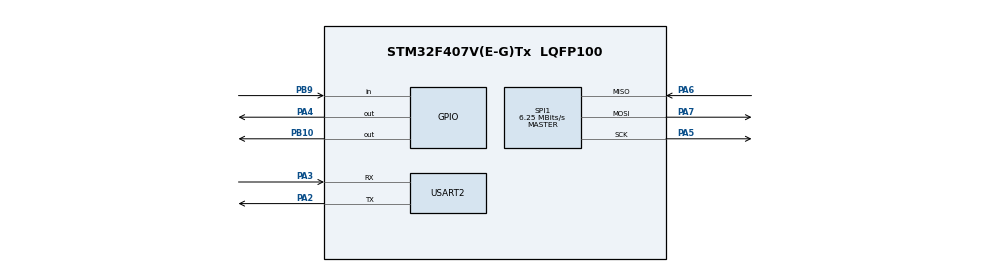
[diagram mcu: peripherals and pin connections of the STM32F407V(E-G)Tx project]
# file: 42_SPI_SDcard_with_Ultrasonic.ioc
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Mcu.Family=STM32F4
Mcu.Name=STM32F407V(E-G)Tx
Mcu.Package=LQFP100
NVIC.PriorityGroup=NVIC_PRIORITYGROUP_0
PA2.Mode=Asynchronous
PA2.Signal=USART2_TX
PA3.Mode=Asynchronous
PA3.Signal=USART2_RX
PA4.Signal=GPIO_Output
PA5.Mode=Full_Duplex_Master
PA5.Signal=SPI1_SCK
PA6.Mode=Full_Duplex_Master
PA6.Signal=SPI1_MISO
PA7.Mode=Full_Duplex_Master
PA7.Signal=SPI1_MOSI
PB10.Signal=GPIO_Output
PB9.Signal=GPIO_Input
PH0-OSC_IN.Mode=HSE-External-Oscillator
PH0-OSC_IN.Signal=RCC_OSC_IN
PH1-OSC_OUT.Mode=HSE-External-Oscillator
PH1-OSC_OUT.Signal=RCC_OSC_OUT
ProjectManager.HeapSize=0x200
ProjectManager.StackSize=0x400
ProjectManager.TargetToolchain=STM32CubeIDE
RCC.48MHZClocksFreq_Value=14285714.285714285
RCC.AHBFreq_Value=25000000
RCC.APB1CLKDivider=RCC_HCLK_DIV4
RCC.APB1Freq_Value=6250000
RCC.APB1TimFreq_Value=12500000
RCC.APB2CLKDivider=RCC_HCLK_DIV2
RCC.APB2Freq_Value=12500000
RCC.APB2TimFreq_Value=25000000
RCC.CortexFreq_Value=25000000
RCC.HCLKFreq_Value=25000000
RCC.HSE_VALUE=8000000
RCC.HSI_VALUE=16000000
RCC.LSE_VALUE=32768
RCC.PLLM=8
RCC.PLLN=50
RCC.PLLP=RCC_PLLP_DIV4
RCC.PLLQ=7
RCC.SYSCLKFreq_VALUE=25000000
RCC.SYSCLKSource=RCC_SYSCLKSOURCE_PLLCLK
RCC.VCOOutputFreq_Value=100000000
SPI1.CalculateBaudRate=6.25 MBits/s
SPI1.Direction=SPI_DIRECTION_2LINES
SPI1.Mode=SPI_MODE_MASTER
SPI1.VirtualType=VM_MASTER
USART2.VirtualMode=VM_ASYNC
VP_FATFS_VS_Generic.Mode=User_defined
VP_TIM3_VS_ClockSourceINT.Mode=Internal
board=STM32F407G-DISC1

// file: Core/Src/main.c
/* USER CODE BEGIN Header */
/* USER CODE END Header */
#include "main.h"
#include "fatfs.h"
#include "stdio.h"
#include "string.h"

/* USER CODE BEGIN PD */
#define TRIG_PORT GPIOB
#define TRIG_PIN  GPIO_PIN_10

#define ECHO_PORT GPIOB
#define ECHO_PIN  GPIO_PIN_9
/* USER CODE END PD */

SPI_HandleTypeDef hspi1;

TIM_HandleTypeDef htim3;

UART_HandleTypeDef huart2;

/* USER CODE BEGIN PV */
FATFS fs;
FIL fil;
FRESULT fres;
UINT bw;

char uart_buf[100];
/* USER CODE END PV */

void SystemClock_Config(void);
static void MX_GPIO_Init(void);
static void MX_SPI1_Init(void);
static void MX_TIM3_Init(void);
static void MX_USART2_UART_Init(void);
void delay_us(uint16_t us);
int get_distance(void);
void UART_Print(char *msg);

/* USER CODE BEGIN 0 */
void UART_Print(char *msg)
{
    HAL_UART_Transmit(&huart2,
                     (uint8_t*)msg,
                     strlen(msg),
                     HAL_MAX_DELAY);
}

void delay_us(uint16_t us)
{
    __HAL_TIM_SET_COUNTER(&htim3,0);

    while(__HAL_TIM_GET_COUNTER(&htim3) < us);
}

int get_distance(void)
{
    uint32_t duration;

    HAL_GPIO_WritePin(TRIG_PORT,TRIG_PIN,GPIO_PIN_RESET);
    delay_us(2);

    HAL_GPIO_WritePin(TRIG_PORT,TRIG_PIN,GPIO_PIN_SET);
    delay_us(10);

    HAL_GPIO_WritePin(TRIG_PORT,TRIG_PIN,GPIO_PIN_RESET);

    while(HAL_GPIO_ReadPin(ECHO_PORT,ECHO_PIN)==GPIO_PIN_RESET);

    __HAL_TIM_SET_COUNTER(&htim3,0);

    while(HAL_GPIO_ReadPin(ECHO_PORT,ECHO_PIN)==GPIO_PIN_SET);

    duration = __HAL_TIM_GET_COUNTER(&htim3);

    return duration/58;
}
/* USER CODE END 0 */

int main(void)
{

  /* MCU Configuration--------------------------------------------------------*/

  /* Reset of all peripherals, Initializes the Flash interface and the Systick. */
  HAL_Init();

  /* Configure the system clock */
  SystemClock_Config();

  /* Initialize all configured peripherals */
  MX_GPIO_Init();
  MX_SPI1_Init();
  MX_TIM3_Init();
  MX_USART2_UART_Init();
  MX_FATFS_Init();
  /* USER CODE BEGIN 2 */
  HAL_TIM_Base_Start(&htim3);

  UART_Print("System Started\r\n");

  fres = f_mount(&fs,"",1);

  if(fres == FR_OK)
  {
      UART_Print("SD Card Mounted\r\n");
  }
  else
  {
      UART_Print("SD Card not Mounted\r\n");
  }
  /* USER CODE END 2 */

  /* Infinite loop */

    /* USER CODE BEGIN 3 */
  while(1)
  {
      int distance = get_distance();

      sprintf(uart_buf,
              "Distance = %d cm\r\n",
              distance);

      UART_Print(uart_buf);

      fres = f_open(&fil,
                    "distance.txt",
                    FA_OPEN_APPEND | FA_WRITE);

      if(fres == FR_OK)
      {
          f_write(&fil,
                  uart_buf,
                  strlen(uart_buf),
                  &bw);

          f_close(&fil);
      }

      HAL_Delay(1000);
  }
  /* USER CODE END 3 */
}

void SystemClock_Config(void)
{
  RCC_OscInitTypeDef RCC_OscInitStruct = {0};
  RCC_ClkInitTypeDef RCC_ClkInitStruct = {0};

  /** Configure the main internal regulator output voltage
  */
  __HAL_RCC_PWR_CLK_ENABLE();
  __HAL_PWR_VOLTAGESCALING_CONFIG(PWR_REGULATOR_VOLTAGE_SCALE1);

  /** Initializes the RCC Oscillators according to the specified parameters
  * in the RCC_OscInitTypeDef structure.
  */
  RCC_OscInitStruct.OscillatorType = RCC_OSCILLATORTYPE_HSE;
  RCC_OscInitStruct.HSEState = RCC_HSE_ON;
  RCC_OscInitStruct.PLL.PLLState = RCC_PLL_ON;
  RCC_OscInitStruct.PLL.PLLSource = RCC_PLLSOURCE_HSE;
  RCC_OscInitStruct.PLL.PLLM = 8;
  RCC_OscInitStruct.PLL.PLLN = 336;
  RCC_OscInitStruct.PLL.PLLP = RCC_PLLP_DIV2;
  RCC_OscInitStruct.PLL.PLLQ = 7;
  if (HAL_RCC_OscConfig(&RCC_OscInitStruct) != HAL_OK)
  {
    Error_Handler();
  }

  /** Initializes the CPU, AHB and APB buses clocks
  */
  RCC_ClkInitStruct.ClockType = RCC_CLOCKTYPE_HCLK|RCC_CLOCKTYPE_SYSCLK
                              |RCC_CLOCKTYPE_PCLK1|RCC_CLOCKTYPE_PCLK2;
  RCC_ClkInitStruct.SYSCLKSource = RCC_SYSCLKSOURCE_PLLCLK;
  RCC_ClkInitStruct.AHBCLKDivider = RCC_SYSCLK_DIV1;
  RCC_ClkInitStruct.APB1CLKDivider = RCC_HCLK_DIV4;
  RCC_ClkInitStruct.APB2CLKDivider = RCC_HCLK_DIV2;

  if (HAL_RCC_ClockConfig(&RCC_ClkInitStruct, FLASH_LATENCY_5) != HAL_OK)
  {
    Error_Handler();
  }
}

static void MX_SPI1_Init(void)
{

  /* SPI1 parameter configuration*/
  hspi1.Instance = SPI1;
  hspi1.Init.Mode = SPI_MODE_MASTER;
  hspi1.Init.Direction = SPI_DIRECTION_2LINES;
  hspi1.Init.DataSize = SPI_DATASIZE_8BIT;
  hspi1.Init.CLKPolarity = SPI_POLARITY_LOW;
  hspi1.Init.CLKPhase = SPI_PHASE_1EDGE;
  hspi1.Init.NSS = SPI_NSS_SOFT;
  hspi1.Init.BaudRatePrescaler = SPI_BAUDRATEPRESCALER_2;
  hspi1.Init.FirstBit = SPI_FIRSTBIT_MSB;
  hspi1.Init.TIMode = SPI_TIMODE_DISABLE;
  hspi1.Init.CRCCalculation = SPI_CRCCALCULATION_DISABLE;
  hspi1.Init.CRCPolynomial = 10;
  if (HAL_SPI_Init(&hspi1) != HAL_OK)
  {
    Error_Handler();
  }

}

static void MX_TIM3_Init(void)
{

  TIM_ClockConfigTypeDef sClockSourceConfig = {0};
  TIM_MasterConfigTypeDef sMasterConfig = {0};

  htim3.Instance = TIM3;
  htim3.Init.Prescaler =  84-1;
  htim3.Init.CounterMode = TIM_COUNTERMODE_UP;
  htim3.Init.Period = 65535;
  htim3.Init.ClockDivision = TIM_CLOCKDIVISION_DIV1;
  htim3.Init.AutoReloadPreload = TIM_AUTORELOAD_PRELOAD_DISABLE;
  if (HAL_TIM_Base_Init(&htim3) != HAL_OK)
  {
    Error_Handler();
  }
  sClockSourceConfig.ClockSource = TIM_CLOCKSOURCE_INTERNAL;
  if (HAL_TIM_ConfigClockSource(&htim3, &sClockSourceConfig) != HAL_OK)
  {
    Error_Handler();
  }
  sMasterConfig.MasterOutputTrigger = TIM_TRGO_RESET;
  sMasterConfig.MasterSlaveMode = TIM_MASTERSLAVEMODE_DISABLE;
  if (HAL_TIMEx_MasterConfigSynchronization(&htim3, &sMasterConfig) != HAL_OK)
  {
    Error_Handler();
  }

}

static void MX_USART2_UART_Init(void)
{

  huart2.Instance = USART2;
  huart2.Init.BaudRate = 115200;
  huart2.Init.WordLength = UART_WORDLENGTH_8B;
  huart2.Init.StopBits = UART_STOPBITS_1;
  huart2.Init.Parity = UART_PARITY_NONE;
  huart2.Init.Mode = UART_MODE_TX_RX;
  huart2.Init.HwFlowCtl = UART_HWCONTROL_NONE;
  huart2.Init.OverSampling = UART_OVERSAMPLING_16;
  if (HAL_UART_Init(&huart2) != HAL_OK)
  {
    Error_Handler();
  }

}

static void MX_GPIO_Init(void)
{
  GPIO_InitTypeDef GPIO_InitStruct = {0};

  /* GPIO Ports Clock Enable */
  __HAL_RCC_GPIOH_CLK_ENABLE();
  __HAL_RCC_GPIOA_CLK_ENABLE();
  __HAL_RCC_GPIOB_CLK_ENABLE();

  /*Configure GPIO pin Output Level */
  HAL_GPIO_WritePin(GPIOA, GPIO_PIN_4, GPIO_PIN_RESET);

  /*Configure GPIO pin Output Level */
  HAL_GPIO_WritePin(GPIOB, GPIO_PIN_10, GPIO_PIN_RESET);

  /*Configure GPIO pin : PA4 */
  GPIO_InitStruct.Pin = GPIO_PIN_4;
  GPIO_InitStruct.Mode = GPIO_MODE_OUTPUT_PP;
  GPIO_InitStruct.Pull = GPIO_NOPULL;
  GPIO_InitStruct.Speed = GPIO_SPEED_FREQ_LOW;
  HAL_GPIO_Init(GPIOA, &GPIO_InitStruct);

  /*Configure GPIO pin : PB10 */
  GPIO_InitStruct.Pin = GPIO_PIN_10;
  GPIO_InitStruct.Mode = GPIO_MODE_OUTPUT_PP;
  GPIO_InitStruct.Pull = GPIO_NOPULL;
  GPIO_InitStruct.Speed = GPIO_SPEED_FREQ_LOW;
  HAL_GPIO_Init(GPIOB, &GPIO_InitStruct);

  /*Configure GPIO pin : PB9 */
  GPIO_InitStruct.Pin = GPIO_PIN_9;
  GPIO_InitStruct.Mode = GPIO_MODE_INPUT;
  GPIO_InitStruct.Pull = GPIO_NOPULL;
  HAL_GPIO_Init(GPIOB, &GPIO_InitStruct);

}

void Error_Handler(void)
{
}
